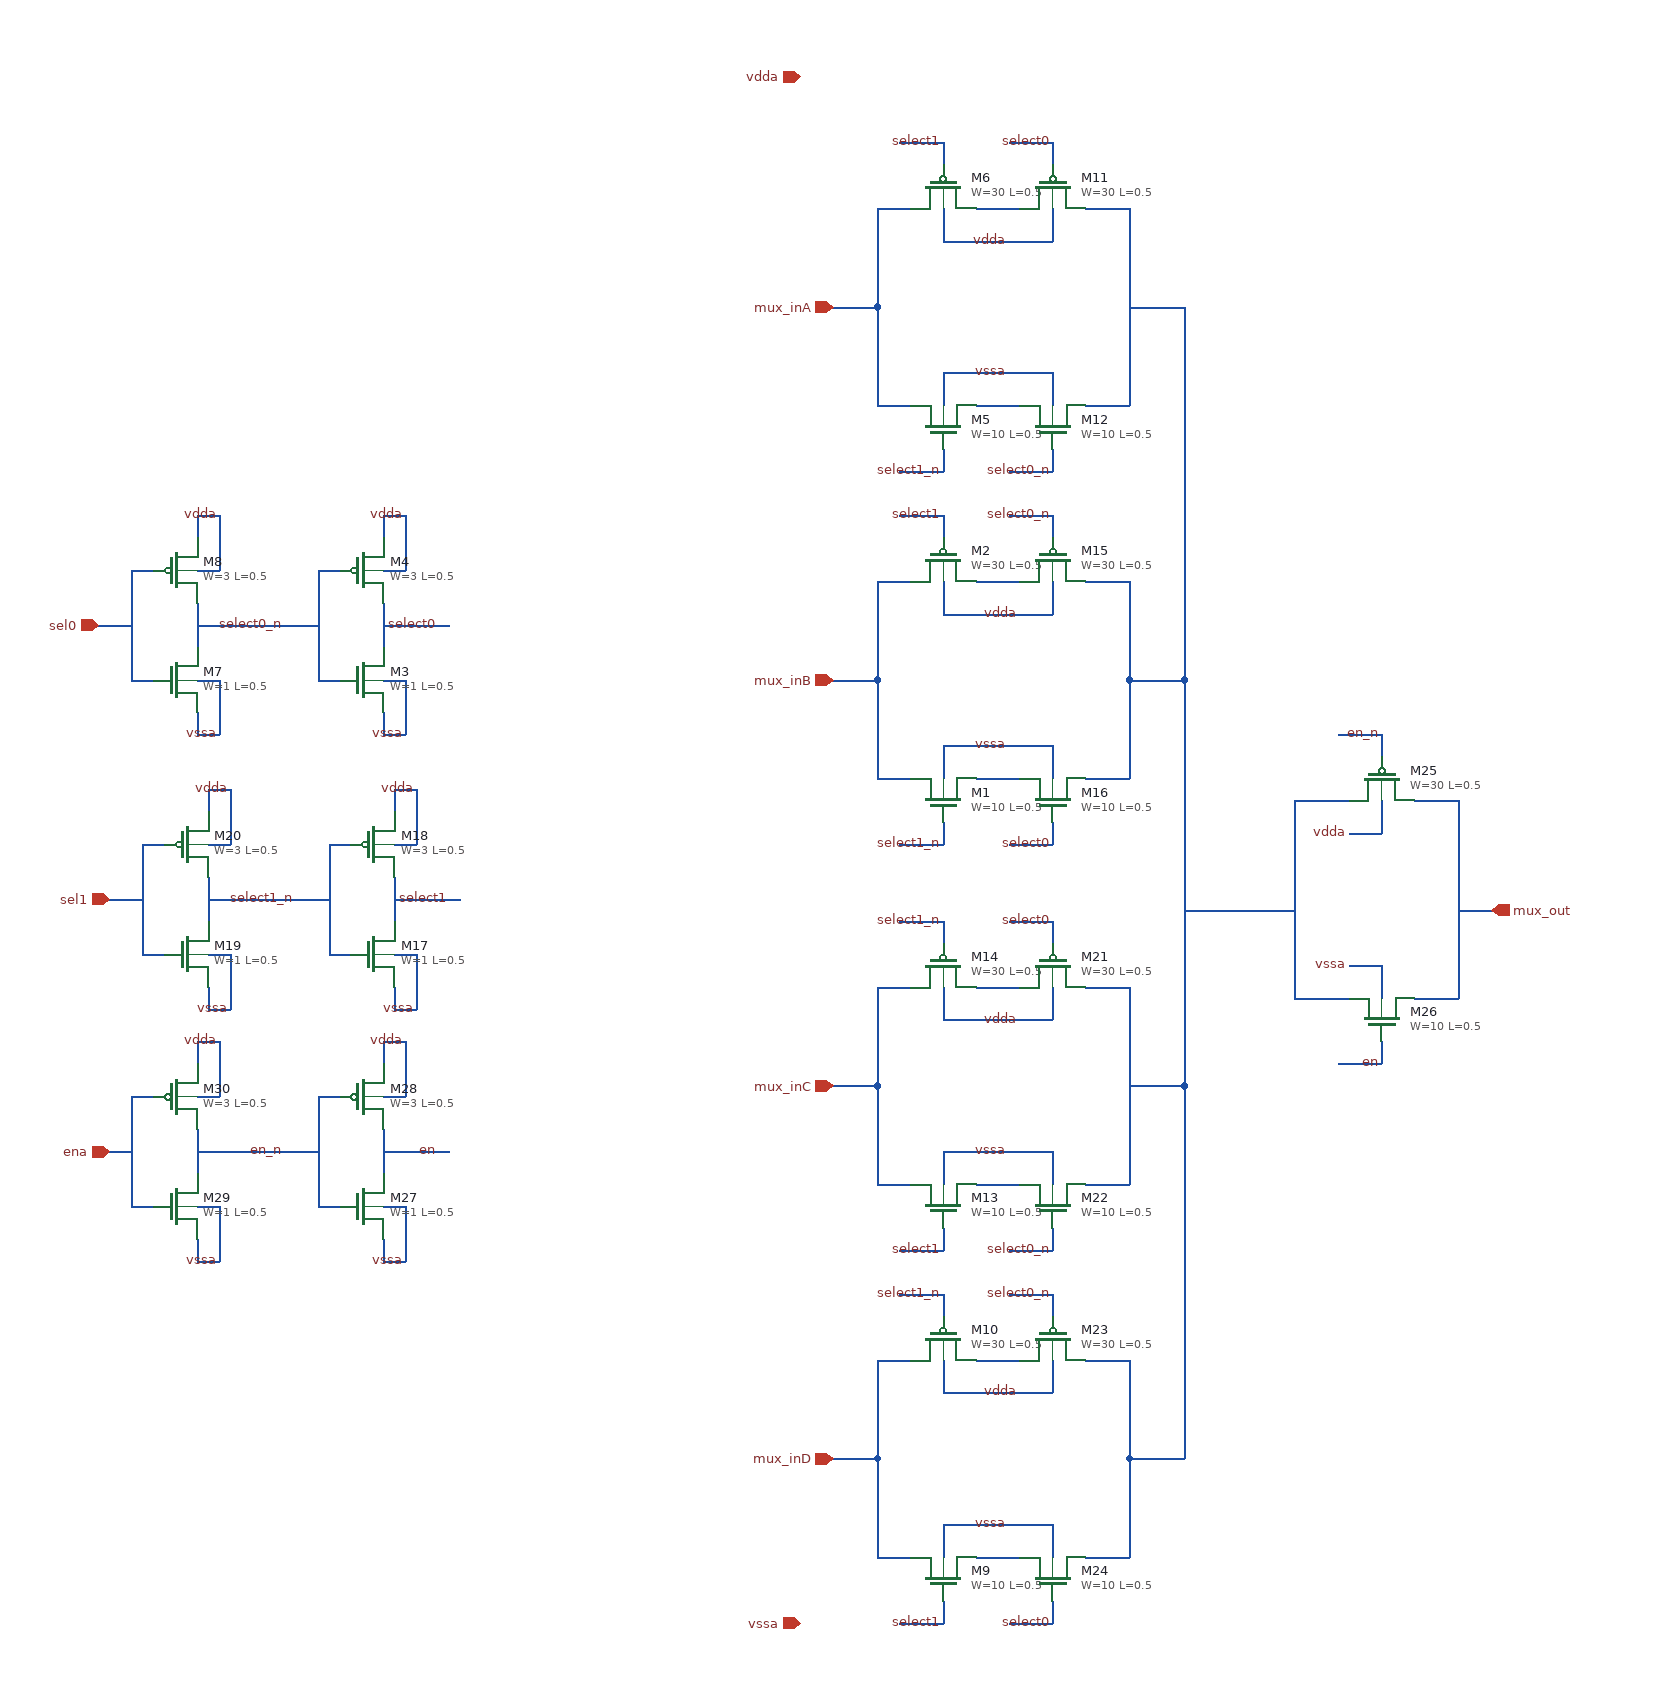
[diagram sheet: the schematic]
v {xschem version=3.4.5 file_version=1.2
}
G {}
K {}
V {}
S {}
E {}
N -60 -300 -30 -300 {
lab=mux_inB}
N -60 -120 -30 -120 {
lab=mux_inB}
N 30 -120 60 -120 {
lab=#net1}
N 30 -300 60 -300 {
lab=#net2}
N 0 -300 0 -270 {
lab=vdda}
N -510 -280 -510 -240 {
lab=select0}
N -570 -310 -550 -310 {
lab=select0_n}
N -570 -310 -570 -210 {
lab=select0_n}
N -570 -210 -550 -210 {
lab=select0_n}
N -510 -260 -450 -260 {
lab=select0}
N -510 -360 -510 -340 {
lab=vdda}
N -510 -310 -490 -310 {
lab=vdda}
N -490 -360 -490 -310 {
lab=vdda}
N -510 -360 -490 -360 {
lab=vdda}
N -510 -210 -490 -210 {
lab=vssa}
N -490 -210 -490 -160 {
lab=vssa}
N -510 -160 -490 -160 {
lab=vssa}
N -510 -180 -510 -160 {
lab=vssa}
N -60 -290 -60 -210 {
lab=mux_inB}
N -60 -640 -30 -640 {
lab=mux_inA}
N -60 -460 -30 -460 {
lab=mux_inA}
N 30 -460 60 -460 {
lab=#net3}
N 30 -640 60 -640 {
lab=#net4}
N 0 -640 0 -610 {
lab=vdda}
N 170 -550 220 -550 {
lab=#net5}
N 170 -560 170 -460 {
lab=#net5}
N -60 -630 -60 -550 {
lab=mux_inA}
N 170 -640 170 -560 {
lab=#net5}
N -0 -700 0 -680 {
lab=select1}
N -40 -700 0 -700 {
lab=select1}
N 0 -420 0 -400 {
lab=select1_n}
N -40 -400 -0 -400 {
lab=select1_n}
N 0 -360 0 -340 {
lab=select1}
N -40 -360 0 -360 {
lab=select1}
N 0 -80 0 -60 {
lab=select1_n}
N -40 -60 0 -60 {
lab=select1_n}
N -60 -640 -60 -630 {
lab=mux_inA}
N -60 -550 -60 -460 {
lab=mux_inA}
N 220 -550 220 -390 {
lab=#net5}
N -60 -300 -60 -290 {
lab=mux_inB}
N -60 -210 -60 -120 {
lab=mux_inB}
N 0 -150 -0 -120 {
lab=vssa}
N -0 -490 -0 -460 {
lab=vssa}
N 220 -390 220 -220 {
lab=#net5}
N 170 -210 220 -210 {
lab=#net5}
N 220 -220 220 -210 {
lab=#net5}
N 170 -300 170 -210 {
lab=#net5}
N 170 -210 170 -120 {
lab=#net5}
N -100 -550 -60 -550 {
lab=mux_inA}
N -100 -210 -60 -210 {
lab=mux_inB}
N -680 -280 -680 -240 {
lab=select0_n}
N -740 -310 -720 -310 {
lab=sel0}
N -740 -310 -740 -210 {
lab=sel0}
N -740 -210 -720 -210 {
lab=sel0}
N -680 -260 -620 -260 {
lab=select0_n}
N -680 -360 -680 -340 {
lab=vdda}
N -680 -310 -660 -310 {
lab=vdda}
N -660 -360 -660 -310 {
lab=vdda}
N -680 -360 -660 -360 {
lab=vdda}
N -680 -210 -660 -210 {
lab=vssa}
N -660 -210 -660 -160 {
lab=vssa}
N -680 -160 -660 -160 {
lab=vssa}
N -680 -180 -680 -160 {
lab=vssa}
N -620 -260 -570 -260 {
lab=select0_n}
N -770 -260 -740 -260 {
lab=sel0}
N -60 410 -30 410 {
lab=mux_inD}
N -60 590 -30 590 {
lab=mux_inD}
N 30 590 60 590 {
lab=#net6}
N 30 410 60 410 {
lab=#net7}
N 0 410 0 440 {
lab=vdda}
N -60 420 -60 500 {
lab=mux_inD}
N -60 70 -30 70 {
lab=mux_inC}
N -60 250 -30 250 {
lab=mux_inC}
N 30 250 60 250 {
lab=#net8}
N 30 70 60 70 {
lab=#net9}
N 0 70 0 100 {
lab=vdda}
N 170 160 220 160 {
lab=#net5}
N 170 150 170 250 {
lab=#net5}
N -60 80 -60 160 {
lab=mux_inC}
N 170 70 170 150 {
lab=#net5}
N 0 10 0 30 {
lab=select1_n}
N -40 10 0 10 {
lab=select1_n}
N 0 290 0 310 {
lab=select1}
N -40 310 0 310 {
lab=select1}
N 0 350 0 370 {
lab=select1_n}
N -40 350 0 350 {
lab=select1_n}
N 0 630 0 650 {
lab=select1}
N -40 650 0 650 {
lab=select1}
N -60 70 -60 80 {
lab=mux_inC}
N -60 160 -60 250 {
lab=mux_inC}
N 220 160 220 320 {
lab=#net5}
N -60 410 -60 420 {
lab=mux_inD}
N -60 500 -60 590 {
lab=mux_inD}
N 0 560 0 590 {
lab=vssa}
N 0 220 0 250 {
lab=vssa}
N 220 320 220 490 {
lab=#net5}
N 170 500 220 500 {
lab=#net5}
N 220 490 220 500 {
lab=#net5}
N 170 410 170 500 {
lab=#net5}
N 170 500 170 590 {
lab=#net5}
N -100 160 -60 160 {
lab=mux_inC}
N -100 500 -60 500 {
lab=mux_inD}
N 220 -210 220 150 {
lab=#net5}
N 220 150 220 160 {
lab=#net5}
N -500 -30 -500 10 {
lab=select1}
N -560 -60 -540 -60 {
lab=select1_n}
N -560 -60 -560 40 {
lab=select1_n}
N -560 40 -540 40 {
lab=select1_n}
N -500 -10 -440 -10 {
lab=select1}
N -500 -110 -500 -90 {
lab=vdda}
N -500 -60 -480 -60 {
lab=vdda}
N -480 -110 -480 -60 {
lab=vdda}
N -500 -110 -480 -110 {
lab=vdda}
N -500 40 -480 40 {
lab=vssa}
N -480 40 -480 90 {
lab=vssa}
N -500 90 -480 90 {
lab=vssa}
N -500 70 -500 90 {
lab=vssa}
N -670 -30 -670 10 {
lab=select1_n}
N -730 -60 -710 -60 {
lab=sel1}
N -730 -60 -730 40 {
lab=sel1}
N -730 40 -710 40 {
lab=sel1}
N -670 -10 -610 -10 {
lab=select1_n}
N -670 -110 -670 -90 {
lab=vdda}
N -670 -60 -650 -60 {
lab=vdda}
N -650 -110 -650 -60 {
lab=vdda}
N -670 -110 -650 -110 {
lab=vdda}
N -670 40 -650 40 {
lab=vssa}
N -650 40 -650 90 {
lab=vssa}
N -670 90 -650 90 {
lab=vssa}
N -670 70 -670 90 {
lab=vssa}
N -610 -10 -560 -10 {
lab=select1_n}
N -760 -10 -730 -10 {
lab=sel1}
N 100 -700 100 -680 {
lab=select0}
N 60 -700 100 -700 {
lab=select0}
N 130 -640 170 -640 {
lab=#net5}
N 60 -640 70 -640 {
lab=#net4}
N 100 -640 100 -610 {
lab=vdda}
N -0 -610 100 -610 {
lab=vdda}
N 130 -460 170 -460 {
lab=#net5}
N 60 -460 70 -460 {
lab=#net3}
N 100 -490 100 -460 {
lab=vssa}
N 0 -490 100 -490 {
lab=vssa}
N 100 -420 100 -400 {
lab=select0_n}
N 60 -400 100 -400 {
lab=select0_n}
N -0 -150 90 -150 {
lab=vssa}
N -0 -270 90 -270 {
lab=vdda}
N 100 -360 100 -340 {
lab=select0_n}
N 60 -360 100 -360 {
lab=select0_n}
N 60 -300 70 -300 {
lab=#net2}
N 130 -300 170 -300 {
lab=#net5}
N 100 -300 100 -270 {
lab=vdda}
N 90 -270 100 -270 {
lab=vdda}
N 130 -120 170 -120 {
lab=#net5}
N 60 -120 70 -120 {
lab=#net1}
N 100 -150 100 -120 {
lab=vssa}
N 90 -150 100 -150 {
lab=vssa}
N 100 -80 100 -60 {
lab=select0}
N 60 -60 100 -60 {
lab=select0}
N 130 70 170 70 {
lab=#net5}
N 100 70 100 100 {
lab=vdda}
N 0 100 100 100 {
lab=vdda}
N 60 70 70 70 {
lab=#net9}
N 100 10 100 30 {
lab=select0}
N 60 10 100 10 {
lab=select0}
N 130 250 170 250 {
lab=#net5}
N 100 220 100 250 {
lab=vssa}
N 0 220 100 220 {
lab=vssa}
N 60 250 70 250 {
lab=#net8}
N 100 290 100 310 {
lab=select0_n}
N 60 310 100 310 {
lab=select0_n}
N 100 350 100 370 {
lab=select0_n}
N 60 350 100 350 {
lab=select0_n}
N 130 410 170 410 {
lab=#net5}
N 60 410 70 410 {
lab=#net7}
N 100 410 100 440 {
lab=vdda}
N -0 440 100 440 {
lab=vdda}
N 130 590 170 590 {
lab=#net5}
N 60 590 70 590 {
lab=#net6}
N 100 560 100 590 {
lab=vssa}
N 0 560 100 560 {
lab=vssa}
N 100 630 100 650 {
lab=#net10}
N 60 650 100 650 {
lab=#net10}
N 330 80 360 80 {
lab=#net5}
N 330 -100 360 -100 {
lab=#net5}
N 400 -160 400 -140 {
lab=en_n}
N 360 -160 400 -160 {
lab=en_n}
N 360 -100 370 -100 {
lab=#net5}
N 400 -100 400 -70 {
lab=vdda}
N 390 -70 400 -70 {
lab=vdda}
N 360 80 370 80 {
lab=#net5}
N 400 50 400 80 {
lab=vssa}
N 390 50 400 50 {
lab=vssa}
N 400 120 400 140 {
lab=en}
N 360 140 400 140 {
lab=en}
N 370 -70 390 -70 {
lab=vdda}
N 370 50 390 50 {
lab=vssa}
N 470 -100 470 80 {
lab=mux_out}
N 320 -100 330 -100 {
lab=#net5}
N 320 80 330 80 {
lab=#net5}
N 440 -100 470 -100 {
lab=mux_out}
N 430 -100 440 -100 {
lab=mux_out}
N 430 80 460 80 {
lab=mux_out}
N 460 80 470 80 {
lab=mux_out}
N 470 0 500 0 {
lab=mux_out}
N 220 -0 320 -0 {
lab=#net5}
N -510 200 -510 240 {
lab=en}
N -570 170 -550 170 {
lab=en_n}
N -570 170 -570 270 {
lab=en_n}
N -570 270 -550 270 {
lab=en_n}
N -510 220 -450 220 {
lab=en}
N -510 120 -510 140 {
lab=vdda}
N -510 170 -490 170 {
lab=vdda}
N -490 120 -490 170 {
lab=vdda}
N -510 120 -490 120 {
lab=vdda}
N -510 270 -490 270 {
lab=vssa}
N -490 270 -490 320 {
lab=vssa}
N -510 320 -490 320 {
lab=vssa}
N -510 300 -510 320 {
lab=vssa}
N -680 200 -680 240 {
lab=en_n}
N -740 170 -720 170 {
lab=ena}
N -740 170 -740 270 {
lab=ena}
N -740 270 -720 270 {
lab=ena}
N -680 220 -620 220 {
lab=en_n}
N -680 120 -680 140 {
lab=vdda}
N -680 170 -660 170 {
lab=vdda}
N -660 120 -660 170 {
lab=vdda}
N -680 120 -660 120 {
lab=vdda}
N -680 270 -660 270 {
lab=vssa}
N -660 270 -660 320 {
lab=vssa}
N -680 320 -660 320 {
lab=vssa}
N -680 300 -680 320 {
lab=vssa}
N -620 220 -570 220 {
lab=en_n}
N -760 220 -740 220 {
lab=ena}
N 320 -100 320 80 {
lab=#net5}
C {sky130_fd_pr/nfet_g5v0d10v5.sym} 0 -100 1 1 {name=M1
L=0.5
W=10
nf=1
mult=1
ad="'int((nf+1)/2) * W/nf * 0.29'" 
pd="'2*int((nf+1)/2) * (W/nf + 0.29)'"
as="'int((nf+2)/2) * W/nf * 0.29'" 
ps="'2*int((nf+2)/2) * (W/nf + 0.29)'"
nrd="'0.29 / W'" nrs="'0.29 / W'"
sa=0 sb=0 sd=0
model=nfet_g5v0d10v5
spiceprefix=X
}
C {sky130_fd_pr/pfet_g5v0d10v5.sym} 0 -320 3 1 {name=M2
L=0.5
W=30
nf=3
mult=1
ad="'int((nf+1)/2) * W/nf * 0.29'" 
pd="'2*int((nf+1)/2) * (W/nf + 0.29)'"
as="'int((nf+2)/2) * W/nf * 0.29'" 
ps="'2*int((nf+2)/2) * (W/nf + 0.29)'"
nrd="'0.29 / W'" nrs="'0.29 / W'"
sa=0 sb=0 sd=0
model=pfet_g5v0d10v5
spiceprefix=X
}
C {sky130_fd_pr/nfet_g5v0d10v5.sym} -530 -210 0 0 {name=M3
L=0.5
W=1
nf=1
mult=1
ad="'int((nf+1)/2) * W/nf * 0.29'" 
pd="'2*int((nf+1)/2) * (W/nf + 0.29)'"
as="'int((nf+2)/2) * W/nf * 0.29'" 
ps="'2*int((nf+2)/2) * (W/nf + 0.29)'"
nrd="'0.29 / W'" nrs="'0.29 / W'"
sa=0 sb=0 sd=0
model=nfet_g5v0d10v5
spiceprefix=X
}
C {sky130_fd_pr/pfet_g5v0d10v5.sym} -530 -310 0 0 {name=M4
L=0.5
W=3
nf=3
mult=1
ad="'int((nf+1)/2) * W/nf * 0.29'" 
pd="'2*int((nf+1)/2) * (W/nf + 0.29)'"
as="'int((nf+2)/2) * W/nf * 0.29'" 
ps="'2*int((nf+2)/2) * (W/nf + 0.29)'"
nrd="'0.29 / W'" nrs="'0.29 / W'"
sa=0 sb=0 sd=0
model=pfet_g5v0d10v5
spiceprefix=X
}
C {devices/lab_wire.sym} -460 -260 0 0 {name=p2 sig_type=std_logic lab=select0}
C {sky130_fd_pr/nfet_g5v0d10v5.sym} 0 -440 1 1 {name=M5
L=0.5
W=10
nf=1
mult=1
ad="'int((nf+1)/2) * W/nf * 0.29'" 
pd="'2*int((nf+1)/2) * (W/nf + 0.29)'"
as="'int((nf+2)/2) * W/nf * 0.29'" 
ps="'2*int((nf+2)/2) * (W/nf + 0.29)'"
nrd="'0.29 / W'" nrs="'0.29 / W'"
sa=0 sb=0 sd=0
model=nfet_g5v0d10v5
spiceprefix=X
}
C {sky130_fd_pr/pfet_g5v0d10v5.sym} 0 -660 3 1 {name=M6
L=0.5
W=30
nf=3
mult=1
ad="'int((nf+1)/2) * W/nf * 0.29'" 
pd="'2*int((nf+1)/2) * (W/nf + 0.29)'"
as="'int((nf+2)/2) * W/nf * 0.29'" 
ps="'2*int((nf+2)/2) * (W/nf + 0.29)'"
nrd="'0.29 / W'" nrs="'0.29 / W'"
sa=0 sb=0 sd=0
model=pfet_g5v0d10v5
spiceprefix=X
}
C {devices/lab_wire.sym} 100 -400 0 0 {name=p8 sig_type=std_logic lab=select0_n}
C {devices/lab_wire.sym} 60 -490 0 0 {name=p7 sig_type=std_logic lab=vssa}
C {devices/lab_wire.sym} 60 -610 0 0 {name=p11 sig_type=std_logic lab=vdda}
C {devices/lab_wire.sym} 60 -150 0 0 {name=p12 sig_type=std_logic lab=vssa}
C {devices/lab_wire.sym} 70 -270 0 0 {name=p13 sig_type=std_logic lab=vdda}
C {devices/lab_wire.sym} -490 -360 0 0 {name=p14 sig_type=std_logic lab=vdda}
C {devices/lab_wire.sym} -490 -160 0 0 {name=p15 sig_type=std_logic lab=vssa}
C {sky130_fd_pr/nfet_g5v0d10v5.sym} -700 -210 0 0 {name=M7
L=0.5
W=1
nf=1
mult=1
ad="'int((nf+1)/2) * W/nf * 0.29'" 
pd="'2*int((nf+1)/2) * (W/nf + 0.29)'"
as="'int((nf+2)/2) * W/nf * 0.29'" 
ps="'2*int((nf+2)/2) * (W/nf + 0.29)'"
nrd="'0.29 / W'" nrs="'0.29 / W'"
sa=0 sb=0 sd=0
model=nfet_g5v0d10v5
spiceprefix=X
}
C {sky130_fd_pr/pfet_g5v0d10v5.sym} -700 -310 0 0 {name=M8
L=0.5
W=3
nf=3
mult=1
ad="'int((nf+1)/2) * W/nf * 0.29'" 
pd="'2*int((nf+1)/2) * (W/nf + 0.29)'"
as="'int((nf+2)/2) * W/nf * 0.29'" 
ps="'2*int((nf+2)/2) * (W/nf + 0.29)'"
nrd="'0.29 / W'" nrs="'0.29 / W'"
sa=0 sb=0 sd=0
model=pfet_g5v0d10v5
spiceprefix=X
}
C {devices/lab_wire.sym} -660 -360 0 0 {name=p19 sig_type=std_logic lab=vdda}
C {devices/lab_wire.sym} -660 -160 0 0 {name=p20 sig_type=std_logic lab=vssa}
C {devices/lab_wire.sym} -600 -260 0 0 {name=p1 sig_type=std_logic lab=select0_n}
C {sky130_fd_pr/nfet_g5v0d10v5.sym} 0 610 1 1 {name=M9
L=0.5
W=10
nf=1
mult=1
ad="'int((nf+1)/2) * W/nf * 0.29'" 
pd="'2*int((nf+1)/2) * (W/nf + 0.29)'"
as="'int((nf+2)/2) * W/nf * 0.29'" 
ps="'2*int((nf+2)/2) * (W/nf + 0.29)'"
nrd="'0.29 / W'" nrs="'0.29 / W'"
sa=0 sb=0 sd=0
model=nfet_g5v0d10v5
spiceprefix=X
}
C {sky130_fd_pr/pfet_g5v0d10v5.sym} 0 390 3 1 {name=M10
L=0.5
W=30
nf=3
mult=1
ad="'int((nf+1)/2) * W/nf * 0.29'" 
pd="'2*int((nf+1)/2) * (W/nf + 0.29)'"
as="'int((nf+2)/2) * W/nf * 0.29'" 
ps="'2*int((nf+2)/2) * (W/nf + 0.29)'"
nrd="'0.29 / W'" nrs="'0.29 / W'"
sa=0 sb=0 sd=0
model=pfet_g5v0d10v5
spiceprefix=X
}
C {sky130_fd_pr/nfet_g5v0d10v5.sym} 0 270 1 1 {name=M13
L=0.5
W=10
nf=1
mult=1
ad="'int((nf+1)/2) * W/nf * 0.29'" 
pd="'2*int((nf+1)/2) * (W/nf + 0.29)'"
as="'int((nf+2)/2) * W/nf * 0.29'" 
ps="'2*int((nf+2)/2) * (W/nf + 0.29)'"
nrd="'0.29 / W'" nrs="'0.29 / W'"
sa=0 sb=0 sd=0
model=nfet_g5v0d10v5
spiceprefix=X
}
C {sky130_fd_pr/pfet_g5v0d10v5.sym} 0 50 3 1 {name=M14
L=0.5
W=30
nf=3
mult=1
ad="'int((nf+1)/2) * W/nf * 0.29'" 
pd="'2*int((nf+1)/2) * (W/nf + 0.29)'"
as="'int((nf+2)/2) * W/nf * 0.29'" 
ps="'2*int((nf+2)/2) * (W/nf + 0.29)'"
nrd="'0.29 / W'" nrs="'0.29 / W'"
sa=0 sb=0 sd=0
model=pfet_g5v0d10v5
spiceprefix=X
}
C {devices/lab_wire.sym} 60 220 0 0 {name=p24 sig_type=std_logic lab=vssa}
C {devices/lab_wire.sym} 70 100 0 0 {name=p25 sig_type=std_logic lab=vdda}
C {devices/lab_wire.sym} 60 560 0 0 {name=p26 sig_type=std_logic lab=vssa}
C {devices/lab_wire.sym} 70 440 0 0 {name=p27 sig_type=std_logic lab=vdda}
C {devices/ipin.sym} -770 -260 0 0 {name=p5 lab=sel0}
C {devices/ipin.sym} -760 -10 0 0 {name=p6 lab=sel1}
C {devices/ipin.sym} -100 -550 0 0 {name=p10 lab=mux_inA}
C {devices/ipin.sym} -100 -210 0 0 {name=p16 lab=mux_inB}
C {devices/ipin.sym} -100 160 0 0 {name=p17 lab=mux_inC}
C {devices/ipin.sym} -100 500 0 0 {name=p18 lab=mux_inD}
C {devices/opin.sym} 500 0 0 0 {name=p30 lab=mux_out}
C {sky130_fd_pr/nfet_g5v0d10v5.sym} -520 40 0 0 {name=M17
L=0.5
W=1
nf=1
mult=1
ad="'int((nf+1)/2) * W/nf * 0.29'" 
pd="'2*int((nf+1)/2) * (W/nf + 0.29)'"
as="'int((nf+2)/2) * W/nf * 0.29'" 
ps="'2*int((nf+2)/2) * (W/nf + 0.29)'"
nrd="'0.29 / W'" nrs="'0.29 / W'"
sa=0 sb=0 sd=0
model=nfet_g5v0d10v5
spiceprefix=X
}
C {sky130_fd_pr/pfet_g5v0d10v5.sym} -520 -60 0 0 {name=M18
L=0.5
W=3
nf=3
mult=1
ad="'int((nf+1)/2) * W/nf * 0.29'" 
pd="'2*int((nf+1)/2) * (W/nf + 0.29)'"
as="'int((nf+2)/2) * W/nf * 0.29'" 
ps="'2*int((nf+2)/2) * (W/nf + 0.29)'"
nrd="'0.29 / W'" nrs="'0.29 / W'"
sa=0 sb=0 sd=0
model=pfet_g5v0d10v5
spiceprefix=X
}
C {devices/lab_wire.sym} -450 -10 0 0 {name=p31 sig_type=std_logic lab=select1}
C {devices/lab_wire.sym} -480 -110 0 0 {name=p32 sig_type=std_logic lab=vdda}
C {devices/lab_wire.sym} -480 90 0 0 {name=p33 sig_type=std_logic lab=vssa}
C {sky130_fd_pr/nfet_g5v0d10v5.sym} -690 40 0 0 {name=M19
L=0.5
W=1
nf=1
mult=1
ad="'int((nf+1)/2) * W/nf * 0.29'" 
pd="'2*int((nf+1)/2) * (W/nf + 0.29)'"
as="'int((nf+2)/2) * W/nf * 0.29'" 
ps="'2*int((nf+2)/2) * (W/nf + 0.29)'"
nrd="'0.29 / W'" nrs="'0.29 / W'"
sa=0 sb=0 sd=0
model=nfet_g5v0d10v5
spiceprefix=X
}
C {sky130_fd_pr/pfet_g5v0d10v5.sym} -690 -60 0 0 {name=M20
L=0.5
W=3
nf=3
mult=1
ad="'int((nf+1)/2) * W/nf * 0.29'" 
pd="'2*int((nf+1)/2) * (W/nf + 0.29)'"
as="'int((nf+2)/2) * W/nf * 0.29'" 
ps="'2*int((nf+2)/2) * (W/nf + 0.29)'"
nrd="'0.29 / W'" nrs="'0.29 / W'"
sa=0 sb=0 sd=0
model=pfet_g5v0d10v5
spiceprefix=X
}
C {devices/lab_wire.sym} -650 -110 0 0 {name=p39 sig_type=std_logic lab=vdda}
C {devices/lab_wire.sym} -650 90 0 0 {name=p40 sig_type=std_logic lab=vssa}
C {devices/lab_wire.sym} -590 -10 0 0 {name=p41 sig_type=std_logic lab=select1_n}
C {sky130_fd_pr/pfet_g5v0d10v5.sym} 100 -660 3 1 {name=M11
L=0.5
W=30
nf=3
mult=1
ad="'int((nf+1)/2) * W/nf * 0.29'" 
pd="'2*int((nf+1)/2) * (W/nf + 0.29)'"
as="'int((nf+2)/2) * W/nf * 0.29'" 
ps="'2*int((nf+2)/2) * (W/nf + 0.29)'"
nrd="'0.29 / W'" nrs="'0.29 / W'"
sa=0 sb=0 sd=0
model=pfet_g5v0d10v5
spiceprefix=X
}
C {sky130_fd_pr/nfet_g5v0d10v5.sym} 100 -440 1 1 {name=M12
L=0.5
W=10
nf=1
mult=1
ad="'int((nf+1)/2) * W/nf * 0.29'" 
pd="'2*int((nf+1)/2) * (W/nf + 0.29)'"
as="'int((nf+2)/2) * W/nf * 0.29'" 
ps="'2*int((nf+2)/2) * (W/nf + 0.29)'"
nrd="'0.29 / W'" nrs="'0.29 / W'"
sa=0 sb=0 sd=0
model=nfet_g5v0d10v5
spiceprefix=X
}
C {sky130_fd_pr/pfet_g5v0d10v5.sym} 100 -320 3 1 {name=M15
L=0.5
W=30
nf=3
mult=1
ad="'int((nf+1)/2) * W/nf * 0.29'" 
pd="'2*int((nf+1)/2) * (W/nf + 0.29)'"
as="'int((nf+2)/2) * W/nf * 0.29'" 
ps="'2*int((nf+2)/2) * (W/nf + 0.29)'"
nrd="'0.29 / W'" nrs="'0.29 / W'"
sa=0 sb=0 sd=0
model=pfet_g5v0d10v5
spiceprefix=X
}
C {sky130_fd_pr/nfet_g5v0d10v5.sym} 100 -100 1 1 {name=M16
L=0.5
W=10
nf=1
mult=1
ad="'int((nf+1)/2) * W/nf * 0.29'" 
pd="'2*int((nf+1)/2) * (W/nf + 0.29)'"
as="'int((nf+2)/2) * W/nf * 0.29'" 
ps="'2*int((nf+2)/2) * (W/nf + 0.29)'"
nrd="'0.29 / W'" nrs="'0.29 / W'"
sa=0 sb=0 sd=0
model=nfet_g5v0d10v5
spiceprefix=X
}
C {sky130_fd_pr/pfet_g5v0d10v5.sym} 100 50 3 1 {name=M21
L=0.5
W=30
nf=3
mult=1
ad="'int((nf+1)/2) * W/nf * 0.29'" 
pd="'2*int((nf+1)/2) * (W/nf + 0.29)'"
as="'int((nf+2)/2) * W/nf * 0.29'" 
ps="'2*int((nf+2)/2) * (W/nf + 0.29)'"
nrd="'0.29 / W'" nrs="'0.29 / W'"
sa=0 sb=0 sd=0
model=pfet_g5v0d10v5
spiceprefix=X
}
C {sky130_fd_pr/nfet_g5v0d10v5.sym} 100 270 1 1 {name=M22
L=0.5
W=10
nf=1
mult=1
ad="'int((nf+1)/2) * W/nf * 0.29'" 
pd="'2*int((nf+1)/2) * (W/nf + 0.29)'"
as="'int((nf+2)/2) * W/nf * 0.29'" 
ps="'2*int((nf+2)/2) * (W/nf + 0.29)'"
nrd="'0.29 / W'" nrs="'0.29 / W'"
sa=0 sb=0 sd=0
model=nfet_g5v0d10v5
spiceprefix=X
}
C {sky130_fd_pr/pfet_g5v0d10v5.sym} 100 390 3 1 {name=M23
L=0.5
W=30
nf=3
mult=1
ad="'int((nf+1)/2) * W/nf * 0.29'" 
pd="'2*int((nf+1)/2) * (W/nf + 0.29)'"
as="'int((nf+2)/2) * W/nf * 0.29'" 
ps="'2*int((nf+2)/2) * (W/nf + 0.29)'"
nrd="'0.29 / W'" nrs="'0.29 / W'"
sa=0 sb=0 sd=0
model=pfet_g5v0d10v5
spiceprefix=X
}
C {sky130_fd_pr/nfet_g5v0d10v5.sym} 100 610 1 1 {name=M24
L=0.5
W=10
nf=1
mult=1
ad="'int((nf+1)/2) * W/nf * 0.29'" 
pd="'2*int((nf+1)/2) * (W/nf + 0.29)'"
as="'int((nf+2)/2) * W/nf * 0.29'" 
ps="'2*int((nf+2)/2) * (W/nf + 0.29)'"
nrd="'0.29 / W'" nrs="'0.29 / W'"
sa=0 sb=0 sd=0
model=nfet_g5v0d10v5
spiceprefix=X
}
C {devices/lab_wire.sym} 0 -400 0 0 {name=p21 sig_type=std_logic lab=select1_n}
C {devices/lab_wire.sym} 100 -700 0 0 {name=p3 sig_type=std_logic lab=select0}
C {devices/lab_wire.sym} 0 -700 0 0 {name=p4 sig_type=std_logic lab=select1}
C {devices/lab_wire.sym} 100 650 0 0 {name=p9 sig_type=std_logic lab=select0}
C {devices/lab_wire.sym} 0 650 0 0 {name=p22 sig_type=std_logic lab=select1}
C {devices/lab_wire.sym} 100 350 0 0 {name=p23 sig_type=std_logic lab=select0_n}
C {devices/lab_wire.sym} 0 350 0 0 {name=p28 sig_type=std_logic lab=select1_n}
C {devices/lab_wire.sym} 100 -60 0 0 {name=p29 sig_type=std_logic lab=select0}
C {devices/lab_wire.sym} 0 -60 0 0 {name=p34 sig_type=std_logic lab=select1_n}
C {devices/lab_wire.sym} 0 -360 0 0 {name=p35 sig_type=std_logic lab=select1}
C {devices/lab_wire.sym} 100 -360 0 0 {name=p36 sig_type=std_logic lab=select0_n}
C {devices/lab_wire.sym} 0 310 0 0 {name=p37 sig_type=std_logic lab=select1}
C {devices/lab_wire.sym} 100 310 0 0 {name=p38 sig_type=std_logic lab=select0_n}
C {devices/lab_wire.sym} 0 10 0 0 {name=p42 sig_type=std_logic lab=select1_n}
C {devices/lab_wire.sym} 100 10 0 0 {name=p43 sig_type=std_logic lab=select0}
C {devices/ipin.sym} -130 -760 0 0 {name=p44 lab=vdda}
C {devices/ipin.sym} -130 650 0 0 {name=p45 lab=vssa}
C {devices/lab_wire.sym} 370 50 0 0 {name=p46 sig_type=std_logic lab=vssa}
C {devices/lab_wire.sym} 370 -70 0 0 {name=p47 sig_type=std_logic lab=vdda}
C {sky130_fd_pr/pfet_g5v0d10v5.sym} 400 -120 3 1 {name=M25
L=0.5
W=30
nf=3
mult=1
ad="'int((nf+1)/2) * W/nf * 0.29'" 
pd="'2*int((nf+1)/2) * (W/nf + 0.29)'"
as="'int((nf+2)/2) * W/nf * 0.29'" 
ps="'2*int((nf+2)/2) * (W/nf + 0.29)'"
nrd="'0.29 / W'" nrs="'0.29 / W'"
sa=0 sb=0 sd=0
model=pfet_g5v0d10v5
spiceprefix=X
}
C {sky130_fd_pr/nfet_g5v0d10v5.sym} 400 100 1 1 {name=M26
L=0.5
W=10
nf=1
mult=1
ad="'int((nf+1)/2) * W/nf * 0.29'" 
pd="'2*int((nf+1)/2) * (W/nf + 0.29)'"
as="'int((nf+2)/2) * W/nf * 0.29'" 
ps="'2*int((nf+2)/2) * (W/nf + 0.29)'"
nrd="'0.29 / W'" nrs="'0.29 / W'"
sa=0 sb=0 sd=0
model=nfet_g5v0d10v5
spiceprefix=X
}
C {devices/lab_wire.sym} 400 140 0 0 {name=p48 sig_type=std_logic lab=en}
C {devices/lab_wire.sym} 400 -160 0 0 {name=p49 sig_type=std_logic lab=en_n}
C {devices/ipin.sym} -760 220 0 0 {name=p50 lab=ena}
C {sky130_fd_pr/nfet_g5v0d10v5.sym} -530 270 0 0 {name=M27
L=0.5
W=1
nf=1
mult=1
ad="'int((nf+1)/2) * W/nf * 0.29'" 
pd="'2*int((nf+1)/2) * (W/nf + 0.29)'"
as="'int((nf+2)/2) * W/nf * 0.29'" 
ps="'2*int((nf+2)/2) * (W/nf + 0.29)'"
nrd="'0.29 / W'" nrs="'0.29 / W'"
sa=0 sb=0 sd=0
model=nfet_g5v0d10v5
spiceprefix=X
}
C {sky130_fd_pr/pfet_g5v0d10v5.sym} -530 170 0 0 {name=M28
L=0.5
W=3
nf=3
mult=1
ad="'int((nf+1)/2) * W/nf * 0.29'" 
pd="'2*int((nf+1)/2) * (W/nf + 0.29)'"
as="'int((nf+2)/2) * W/nf * 0.29'" 
ps="'2*int((nf+2)/2) * (W/nf + 0.29)'"
nrd="'0.29 / W'" nrs="'0.29 / W'"
sa=0 sb=0 sd=0
model=pfet_g5v0d10v5
spiceprefix=X
}
C {devices/lab_wire.sym} -460 220 0 0 {name=p51 sig_type=std_logic lab=en}
C {devices/lab_wire.sym} -490 120 0 0 {name=p52 sig_type=std_logic lab=vdda}
C {devices/lab_wire.sym} -490 320 0 0 {name=p53 sig_type=std_logic lab=vssa}
C {sky130_fd_pr/nfet_g5v0d10v5.sym} -700 270 0 0 {name=M29
L=0.5
W=1
nf=1
mult=1
ad="'int((nf+1)/2) * W/nf * 0.29'" 
pd="'2*int((nf+1)/2) * (W/nf + 0.29)'"
as="'int((nf+2)/2) * W/nf * 0.29'" 
ps="'2*int((nf+2)/2) * (W/nf + 0.29)'"
nrd="'0.29 / W'" nrs="'0.29 / W'"
sa=0 sb=0 sd=0
model=nfet_g5v0d10v5
spiceprefix=X
}
C {sky130_fd_pr/pfet_g5v0d10v5.sym} -700 170 0 0 {name=M30
L=0.5
W=3
nf=3
mult=1
ad="'int((nf+1)/2) * W/nf * 0.29'" 
pd="'2*int((nf+1)/2) * (W/nf + 0.29)'"
as="'int((nf+2)/2) * W/nf * 0.29'" 
ps="'2*int((nf+2)/2) * (W/nf + 0.29)'"
nrd="'0.29 / W'" nrs="'0.29 / W'"
sa=0 sb=0 sd=0
model=pfet_g5v0d10v5
spiceprefix=X
}
C {devices/lab_wire.sym} -660 120 0 0 {name=p54 sig_type=std_logic lab=vdda}
C {devices/lab_wire.sym} -660 320 0 0 {name=p55 sig_type=std_logic lab=vssa}
C {devices/lab_wire.sym} -600 220 0 0 {name=p56 sig_type=std_logic lab=en_n}
